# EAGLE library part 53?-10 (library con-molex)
CONNECTOR wire to board 1.25 mm (.049 inch) pitch header

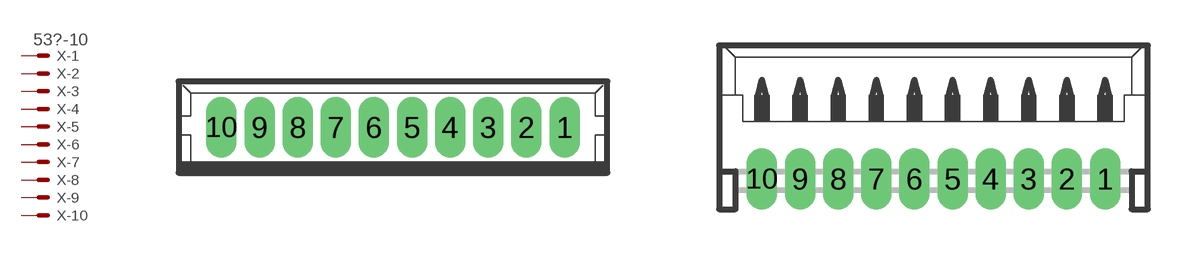
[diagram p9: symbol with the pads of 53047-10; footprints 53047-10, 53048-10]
Designator prefix X; gates -1=MV -2=M -3=M -4=M -5=M -6=M -7=M -8=M -9=M -10=M

## 53047-10  [53047-10]
1  -1:S  pas
2  -2:S  pas
3  -3:S  pas
4  -4:S  pas
5  -5:S  pas
6  -6:S  pas
7  -7:S  pas
8  -8:S  pas
9  -9:S  pas
10  -10:S  pas

## 53048-10  [53048-10]
Pads as for 53047-10

## 53261-10  [53261-10]
Pads as for 53047-10

## 53398-10  [53398-10]
Pads as for 53047-10

## Footprint 53047-10 (pad centres in mm)
CONNECTOR wire to board 1.25 mm (.049 inch) pitch header straight
drill 0.5 pad 0.698 long: 1 5.625,0; 2 4.375,0; 3 3.125,0; 4 1.875,0; 5 0.625,0; 6 -0.625,0; 7 -1.875,0; 8 -3.125,0; 9 -4.375,0; 10 -5.625,0

## Footprint 53048-10 (pad centres in mm)
CONNECTOR wire to board 1.25 mm (.049 inch) pitch header right angle
drill 0.5 pad 0.698 long: 1 5.625,-1.25; 2 4.375,-1.25; 3 3.125,-1.25; 4 1.875,-1.25; 5 0.625,-1.25; 6 -0.625,-1.25; 7 -1.875,-1.25; 8 -3.125,-1.25; 9 -4.375,-1.25; 10 -5.625,-1.25

## Footprint 53261-10 (pad centres in mm)
CONNECTOR wire to board 1.25 mm (.049 inch) pitch header SMT right angle
smd 0.8 x 2: 1 5.625,-2.5; 2 4.375,-2.5; 3 3.125,-2.5; 4 1.875,-2.5; 5 0.625,-2.5; 6 -0.625,-2.5; 7 -1.875,-2.5; 8 -3.125,-2.5; 9 -4.375,-2.5; 10 -5.625,-2.5
smd 2.1 x 3: S1 8.125,0.625; S2 -8.125,0.625

## Footprint 53398-10 (pad centres in mm)
CONNECTOR wire to board 1.25 mm (.049 inch) pitch header SMT straight
smd 0.8 x 1.8: 1 5.625,-2.5; 2 4.375,-2.5; 3 3.125,-2.5; 4 1.875,-2.5; 5 0.625,-2.5; 6 -0.625,-2.5; 7 -1.875,-2.5; 8 -3.125,-2.5; 9 -4.375,-2.5; 10 -5.625,-2.5
smd 2.1 x 3: S1 8.125,0.625; S2 -8.125,0.625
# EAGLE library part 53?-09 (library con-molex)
CONNECTOR wire to board 1.25 mm (.049 inch) pitch header

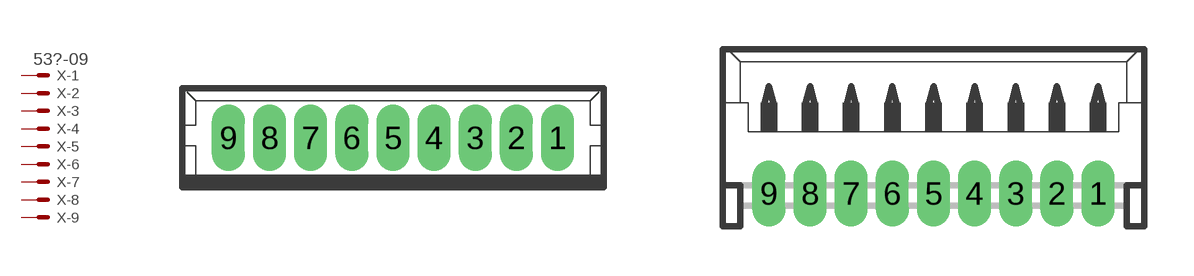
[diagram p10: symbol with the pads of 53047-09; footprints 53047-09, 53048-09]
Designator prefix X; gates -1=MV -2=M -3=M -4=M -5=M -6=M -7=M -8=M -9=M

## 53047-09  [53047-09]
1  -1:S  pas
2  -2:S  pas
3  -3:S  pas
4  -4:S  pas
5  -5:S  pas
6  -6:S  pas
7  -7:S  pas
8  -8:S  pas
9  -9:S  pas

## 53048-09  [53048-09]
Pads as for 53047-09

## 53261-09  [53261-09]
Pads as for 53047-09

## 53398-09  [53398-09]
Pads as for 53047-09

## Footprint 53047-09 (pad centres in mm)
CONNECTOR wire to board 1.25 mm (.049 inch) pitch header straight
drill 0.5 pad 0.698 long: 1 5,0; 2 3.75,0; 3 2.5,0; 4 1.25,0; 5 0,0; 6 -1.25,0; 7 -2.5,0; 8 -3.75,0; 9 -5,0

## Footprint 53048-09 (pad centres in mm)
CONNECTOR wire to board 1.25 mm (.049 inch) pitch header right angle
drill 0.5 pad 0.698 long: 1 5,-1.25; 2 3.75,-1.25; 3 2.5,-1.25; 4 1.25,-1.25; 5 0,-1.25; 6 -1.25,-1.25; 7 -2.5,-1.25; 8 -3.75,-1.25; 9 -5,-1.25

## Footprint 53261-09 (pad centres in mm)
CONNECTOR wire to board 1.25 mm (.049 inch) pitch header SMT right angle
smd 0.8 x 2: 1 5,-2.5; 2 3.75,-2.5; 3 2.5,-2.5; 4 1.25,-2.5; 5 0,-2.5; 6 -1.25,-2.5; 7 -2.5,-2.5; 8 -3.75,-2.5; 9 -5,-2.5
smd 2.1 x 3: S1 7.5,0.625; S2 -7.5,0.625

## Footprint 53398-09 (pad centres in mm)
CONNECTOR wire to board 1.25 mm (.049 inch) pitch header SMT straight
smd 0.8 x 1.8: 1 5,-2.5; 2 3.75,-2.5; 3 2.5,-2.5; 4 1.25,-2.5; 5 0,-2.5; 6 -1.25,-2.5; 7 -2.5,-2.5; 8 -3.75,-2.5; 9 -5,-2.5
smd 2.1 x 3: S1 7.5,0.625; S2 -7.5,0.625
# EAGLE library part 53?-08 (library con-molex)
CONNECTOR wire to board 1.25 mm (.049 inch) pitch header

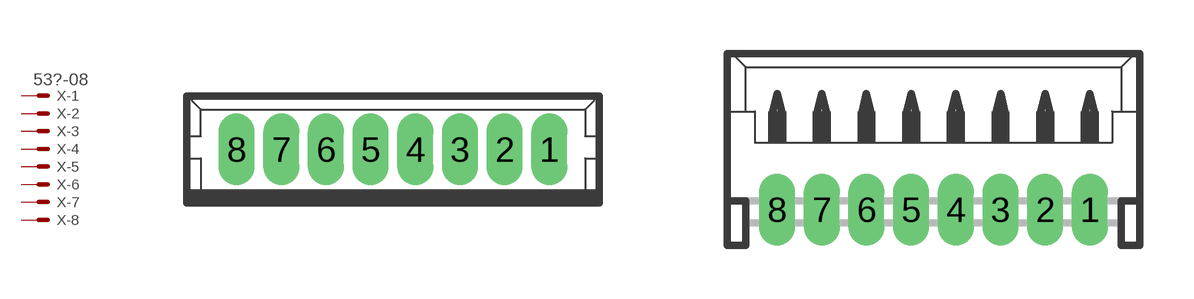
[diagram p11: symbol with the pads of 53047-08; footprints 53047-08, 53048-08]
Designator prefix X; gates -1=MV -2=M -3=M -4=M -5=M -6=M -7=M -8=M

## 53047-08  [53047-08]
1  -1:S  pas
2  -2:S  pas
3  -3:S  pas
4  -4:S  pas
5  -5:S  pas
6  -6:S  pas
7  -7:S  pas
8  -8:S  pas

## 53048-08  [53048-08]
Pads as for 53047-08

## 53261-08  [53261-08]
Pads as for 53047-08

## 53398-08  [53398-08]
Pads as for 53047-08

## Footprint 53047-08 (pad centres in mm)
CONNECTOR wire to board 1.25 mm (.049 inch) pitch header straight
drill 0.5 pad 0.698 long: 1 4.375,0; 2 3.125,0; 3 1.875,0; 4 0.625,0; 5 -0.625,0; 6 -1.875,0; 7 -3.125,0; 8 -4.375,0

## Footprint 53048-08 (pad centres in mm)
CONNECTOR wire to board 1.25 mm (.049 inch) pitch header right angle
drill 0.5 pad 0.698 long: 1 4.375,-1.25; 2 3.125,-1.25; 3 1.875,-1.25; 4 0.625,-1.25; 5 -0.625,-1.25; 6 -1.875,-1.25; 7 -3.125,-1.25; 8 -4.375,-1.25

## Footprint 53261-08 (pad centres in mm)
CONNECTOR wire to board 1.25 mm (.049 inch) pitch header SMT right angle
smd 0.8 x 2: 1 4.375,-2.5; 2 3.125,-2.5; 3 1.875,-2.5; 4 0.625,-2.5; 5 -0.625,-2.5; 6 -1.875,-2.5; 7 -3.125,-2.5; 8 -4.375,-2.5
smd 2.1 x 3: S1 6.875,0.625; S2 -6.875,0.625

## Footprint 53398-08 (pad centres in mm)
CONNECTOR wire to board 1.25 mm (.049 inch) pitch header SMT straight
smd 0.8 x 1.8: 1 4.375,-2.5; 2 3.125,-2.5; 3 1.875,-2.5; 4 0.625,-2.5; 5 -0.625,-2.5; 6 -1.875,-2.5; 7 -3.125,-2.5; 8 -4.375,-2.5
smd 2.1 x 3: S1 6.875,0.625; S2 -6.875,0.625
